VERSION 5.7 ;
  NOWIREEXTENSIONATPIN ON ;
  DIVIDERCHAR "/" ;
  BUSBITCHARS "[]" ;
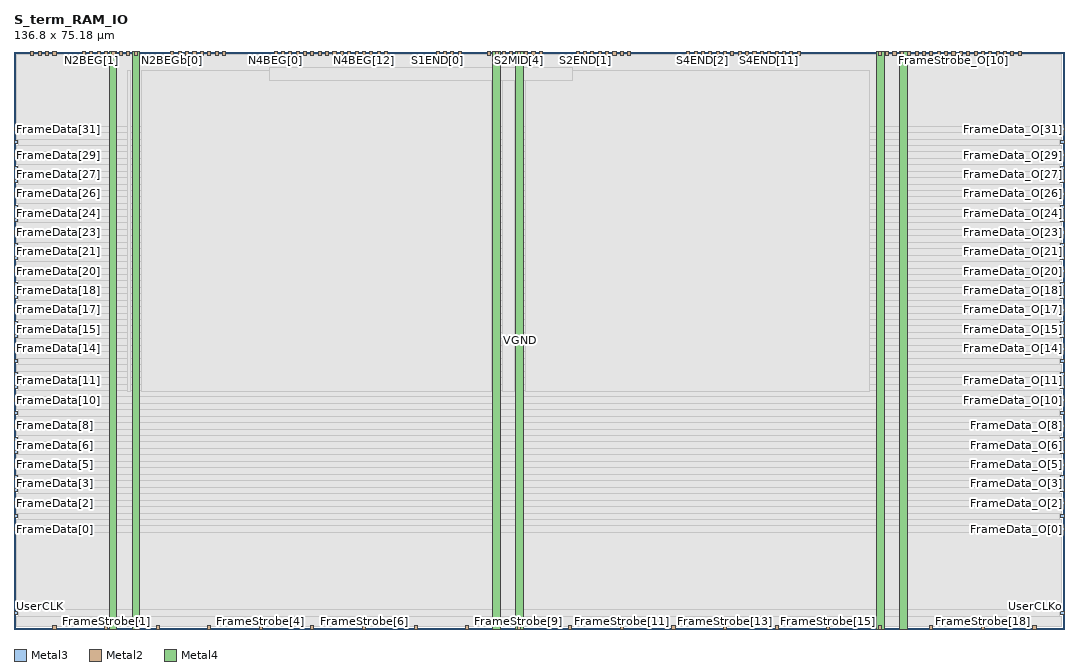
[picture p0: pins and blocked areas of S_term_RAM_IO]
MACRO S_term_RAM_IO
  CLASS BLOCK ;
  FOREIGN S_term_RAM_IO ;
  ORIGIN 0.000 0.000 ;
  SIZE 136.800 BY 75.180 ;
  PIN FrameData[0]
    DIRECTION INPUT ;
    USE SIGNAL ;
    ANTENNAGATEAREA 0.180700 ;
    PORT
      LAYER Metal3 ;
        RECT 0.000 12.820 0.400 13.220 ;
    END
  END FrameData[0]
  PIN FrameData[10]
    DIRECTION INPUT ;
    USE SIGNAL ;
    ANTENNAGATEAREA 0.180700 ;
    PORT
      LAYER Metal3 ;
        RECT 0.000 29.620 0.400 30.020 ;
    END
  END FrameData[10]
  PIN FrameData[11]
    DIRECTION INPUT ;
    USE SIGNAL ;
    ANTENNAGATEAREA 0.180700 ;
    PORT
      LAYER Metal3 ;
        RECT 0.000 31.300 0.400 31.700 ;
    END
  END FrameData[11]
  PIN FrameData[12]
    DIRECTION INPUT ;
    USE SIGNAL ;
    ANTENNAGATEAREA 0.180700 ;
    PORT
      LAYER Metal3 ;
        RECT 0.000 32.980 0.400 33.380 ;
    END
  END FrameData[12]
  PIN FrameData[13]
    DIRECTION INPUT ;
    USE SIGNAL ;
    ANTENNAGATEAREA 0.180700 ;
    PORT
      LAYER Metal3 ;
        RECT 0.000 34.660 0.400 35.060 ;
    END
  END FrameData[13]
  PIN FrameData[14]
    DIRECTION INPUT ;
    USE SIGNAL ;
    ANTENNAGATEAREA 0.180700 ;
    PORT
      LAYER Metal3 ;
        RECT 0.000 36.340 0.400 36.740 ;
    END
  END FrameData[14]
  PIN FrameData[15]
    DIRECTION INPUT ;
    USE SIGNAL ;
    ANTENNAGATEAREA 0.180700 ;
    PORT
      LAYER Metal3 ;
        RECT 0.000 38.020 0.400 38.420 ;
    END
  END FrameData[15]
  PIN FrameData[16]
    DIRECTION INPUT ;
    USE SIGNAL ;
    ANTENNAGATEAREA 0.180700 ;
    PORT
      LAYER Metal3 ;
        RECT 0.000 39.700 0.400 40.100 ;
    END
  END FrameData[16]
  PIN FrameData[17]
    DIRECTION INPUT ;
    USE SIGNAL ;
    ANTENNAGATEAREA 0.180700 ;
    PORT
      LAYER Metal3 ;
        RECT 0.000 41.380 0.400 41.780 ;
    END
  END FrameData[17]
  PIN FrameData[18]
    DIRECTION INPUT ;
    USE SIGNAL ;
    ANTENNAGATEAREA 0.180700 ;
    PORT
      LAYER Metal3 ;
        RECT 0.000 43.060 0.400 43.460 ;
    END
  END FrameData[18]
  PIN FrameData[19]
    DIRECTION INPUT ;
    USE SIGNAL ;
    ANTENNAGATEAREA 0.180700 ;
    PORT
      LAYER Metal3 ;
        RECT 0.000 44.740 0.400 45.140 ;
    END
  END FrameData[19]
  PIN FrameData[1]
    DIRECTION INPUT ;
    USE SIGNAL ;
    ANTENNAGATEAREA 0.180700 ;
    PORT
      LAYER Metal3 ;
        RECT 0.000 14.500 0.400 14.900 ;
    END
  END FrameData[1]
  PIN FrameData[20]
    DIRECTION INPUT ;
    USE SIGNAL ;
    ANTENNAGATEAREA 0.180700 ;
    PORT
      LAYER Metal3 ;
        RECT 0.000 46.420 0.400 46.820 ;
    END
  END FrameData[20]
  PIN FrameData[21]
    DIRECTION INPUT ;
    USE SIGNAL ;
    ANTENNAGATEAREA 0.180700 ;
    PORT
      LAYER Metal3 ;
        RECT 0.000 48.100 0.400 48.500 ;
    END
  END FrameData[21]
  PIN FrameData[22]
    DIRECTION INPUT ;
    USE SIGNAL ;
    ANTENNAGATEAREA 0.180700 ;
    PORT
      LAYER Metal3 ;
        RECT 0.000 49.780 0.400 50.180 ;
    END
  END FrameData[22]
  PIN FrameData[23]
    DIRECTION INPUT ;
    USE SIGNAL ;
    ANTENNAGATEAREA 0.180700 ;
    PORT
      LAYER Metal3 ;
        RECT 0.000 51.460 0.400 51.860 ;
    END
  END FrameData[23]
  PIN FrameData[24]
    DIRECTION INPUT ;
    USE SIGNAL ;
    ANTENNAGATEAREA 0.180700 ;
    PORT
      LAYER Metal3 ;
        RECT 0.000 53.140 0.400 53.540 ;
    END
  END FrameData[24]
  PIN FrameData[25]
    DIRECTION INPUT ;
    USE SIGNAL ;
    ANTENNAGATEAREA 0.180700 ;
    PORT
      LAYER Metal3 ;
        RECT 0.000 54.820 0.400 55.220 ;
    END
  END FrameData[25]
  PIN FrameData[26]
    DIRECTION INPUT ;
    USE SIGNAL ;
    ANTENNAGATEAREA 0.180700 ;
    PORT
      LAYER Metal3 ;
        RECT 0.000 56.500 0.400 56.900 ;
    END
  END FrameData[26]
  PIN FrameData[27]
    DIRECTION INPUT ;
    USE SIGNAL ;
    ANTENNAGATEAREA 0.180700 ;
    PORT
      LAYER Metal3 ;
        RECT 0.000 58.180 0.400 58.580 ;
    END
  END FrameData[27]
  PIN FrameData[28]
    DIRECTION INPUT ;
    USE SIGNAL ;
    ANTENNAGATEAREA 0.180700 ;
    PORT
      LAYER Metal3 ;
        RECT 0.000 59.860 0.400 60.260 ;
    END
  END FrameData[28]
  PIN FrameData[29]
    DIRECTION INPUT ;
    USE SIGNAL ;
    ANTENNAGATEAREA 0.180700 ;
    PORT
      LAYER Metal3 ;
        RECT 0.000 61.540 0.400 61.940 ;
    END
  END FrameData[29]
  PIN FrameData[2]
    DIRECTION INPUT ;
    USE SIGNAL ;
    ANTENNAGATEAREA 0.180700 ;
    PORT
      LAYER Metal3 ;
        RECT 0.000 16.180 0.400 16.580 ;
    END
  END FrameData[2]
  PIN FrameData[30]
    DIRECTION INPUT ;
    USE SIGNAL ;
    ANTENNAGATEAREA 0.180700 ;
    PORT
      LAYER Metal3 ;
        RECT 0.000 63.220 0.400 63.620 ;
    END
  END FrameData[30]
  PIN FrameData[31]
    DIRECTION INPUT ;
    USE SIGNAL ;
    ANTENNAGATEAREA 0.180700 ;
    PORT
      LAYER Metal3 ;
        RECT 0.000 64.900 0.400 65.300 ;
    END
  END FrameData[31]
  PIN FrameData[3]
    DIRECTION INPUT ;
    USE SIGNAL ;
    ANTENNAGATEAREA 0.180700 ;
    PORT
      LAYER Metal3 ;
        RECT 0.000 17.860 0.400 18.260 ;
    END
  END FrameData[3]
  PIN FrameData[4]
    DIRECTION INPUT ;
    USE SIGNAL ;
    ANTENNAGATEAREA 0.180700 ;
    PORT
      LAYER Metal3 ;
        RECT 0.000 19.540 0.400 19.940 ;
    END
  END FrameData[4]
  PIN FrameData[5]
    DIRECTION INPUT ;
    USE SIGNAL ;
    ANTENNAGATEAREA 0.180700 ;
    PORT
      LAYER Metal3 ;
        RECT 0.000 21.220 0.400 21.620 ;
    END
  END FrameData[5]
  PIN FrameData[6]
    DIRECTION INPUT ;
    USE SIGNAL ;
    ANTENNAGATEAREA 0.180700 ;
    PORT
      LAYER Metal3 ;
        RECT 0.000 22.900 0.400 23.300 ;
    END
  END FrameData[6]
  PIN FrameData[7]
    DIRECTION INPUT ;
    USE SIGNAL ;
    ANTENNAGATEAREA 0.180700 ;
    PORT
      LAYER Metal3 ;
        RECT 0.000 24.580 0.400 24.980 ;
    END
  END FrameData[7]
  PIN FrameData[8]
    DIRECTION INPUT ;
    USE SIGNAL ;
    ANTENNAGATEAREA 0.180700 ;
    PORT
      LAYER Metal3 ;
        RECT 0.000 26.260 0.400 26.660 ;
    END
  END FrameData[8]
  PIN FrameData[9]
    DIRECTION INPUT ;
    USE SIGNAL ;
    ANTENNAGATEAREA 0.180700 ;
    PORT
      LAYER Metal3 ;
        RECT 0.000 27.940 0.400 28.340 ;
    END
  END FrameData[9]
  PIN FrameData_O[0]
    DIRECTION OUTPUT ;
    USE SIGNAL ;
    ANTENNADIFFAREA 2.724000 ;
    PORT
      LAYER Metal3 ;
        RECT 136.400 12.820 136.800 13.220 ;
    END
  END FrameData_O[0]
  PIN FrameData_O[10]
    DIRECTION OUTPUT ;
    USE SIGNAL ;
    ANTENNADIFFAREA 2.724000 ;
    PORT
      LAYER Metal3 ;
        RECT 136.400 29.620 136.800 30.020 ;
    END
  END FrameData_O[10]
  PIN FrameData_O[11]
    DIRECTION OUTPUT ;
    USE SIGNAL ;
    ANTENNADIFFAREA 2.724000 ;
    PORT
      LAYER Metal3 ;
        RECT 136.400 31.300 136.800 31.700 ;
    END
  END FrameData_O[11]
  PIN FrameData_O[12]
    DIRECTION OUTPUT ;
    USE SIGNAL ;
    ANTENNADIFFAREA 2.724000 ;
    PORT
      LAYER Metal3 ;
        RECT 136.400 32.980 136.800 33.380 ;
    END
  END FrameData_O[12]
  PIN FrameData_O[13]
    DIRECTION OUTPUT ;
    USE SIGNAL ;
    ANTENNADIFFAREA 2.724000 ;
    PORT
      LAYER Metal3 ;
        RECT 136.400 34.660 136.800 35.060 ;
    END
  END FrameData_O[13]
  PIN FrameData_O[14]
    DIRECTION OUTPUT ;
    USE SIGNAL ;
    ANTENNADIFFAREA 2.724000 ;
    PORT
      LAYER Metal3 ;
        RECT 136.400 36.340 136.800 36.740 ;
    END
  END FrameData_O[14]
  PIN FrameData_O[15]
    DIRECTION OUTPUT ;
    USE SIGNAL ;
    ANTENNADIFFAREA 2.724000 ;
    PORT
      LAYER Metal3 ;
        RECT 136.400 38.020 136.800 38.420 ;
    END
  END FrameData_O[15]
  PIN FrameData_O[16]
    DIRECTION OUTPUT ;
    USE SIGNAL ;
    ANTENNADIFFAREA 2.724000 ;
    PORT
      LAYER Metal3 ;
        RECT 136.400 39.700 136.800 40.100 ;
    END
  END FrameData_O[16]
  PIN FrameData_O[17]
    DIRECTION OUTPUT ;
    USE SIGNAL ;
    ANTENNADIFFAREA 2.724000 ;
    PORT
      LAYER Metal3 ;
        RECT 136.400 41.380 136.800 41.780 ;
    END
  END FrameData_O[17]
  PIN FrameData_O[18]
    DIRECTION OUTPUT ;
    USE SIGNAL ;
    ANTENNADIFFAREA 2.724000 ;
    PORT
      LAYER Metal3 ;
        RECT 136.400 43.060 136.800 43.460 ;
    END
  END FrameData_O[18]
  PIN FrameData_O[19]
    DIRECTION OUTPUT ;
    USE SIGNAL ;
    ANTENNADIFFAREA 2.724000 ;
    PORT
      LAYER Metal3 ;
        RECT 136.400 44.740 136.800 45.140 ;
    END
  END FrameData_O[19]
  PIN FrameData_O[1]
    DIRECTION OUTPUT ;
    USE SIGNAL ;
    ANTENNADIFFAREA 2.724000 ;
    PORT
      LAYER Metal3 ;
        RECT 136.400 14.500 136.800 14.900 ;
    END
  END FrameData_O[1]
  PIN FrameData_O[20]
    DIRECTION OUTPUT ;
    USE SIGNAL ;
    ANTENNADIFFAREA 2.724000 ;
    PORT
      LAYER Metal3 ;
        RECT 136.400 46.420 136.800 46.820 ;
    END
  END FrameData_O[20]
  PIN FrameData_O[21]
    DIRECTION OUTPUT ;
    USE SIGNAL ;
    ANTENNADIFFAREA 2.724000 ;
    PORT
      LAYER Metal3 ;
        RECT 136.400 48.100 136.800 48.500 ;
    END
  END FrameData_O[21]
  PIN FrameData_O[22]
    DIRECTION OUTPUT ;
    USE SIGNAL ;
    ANTENNADIFFAREA 2.724000 ;
    PORT
      LAYER Metal3 ;
        RECT 136.400 49.780 136.800 50.180 ;
    END
  END FrameData_O[22]
  PIN FrameData_O[23]
    DIRECTION OUTPUT ;
    USE SIGNAL ;
    ANTENNADIFFAREA 2.724000 ;
    PORT
      LAYER Metal3 ;
        RECT 136.400 51.460 136.800 51.860 ;
    END
  END FrameData_O[23]
  PIN FrameData_O[24]
    DIRECTION OUTPUT ;
    USE SIGNAL ;
    ANTENNADIFFAREA 2.724000 ;
    PORT
      LAYER Metal3 ;
        RECT 136.400 53.140 136.800 53.540 ;
    END
  END FrameData_O[24]
  PIN FrameData_O[25]
    DIRECTION OUTPUT ;
    USE SIGNAL ;
    ANTENNADIFFAREA 2.724000 ;
    PORT
      LAYER Metal3 ;
        RECT 136.400 54.820 136.800 55.220 ;
    END
  END FrameData_O[25]
  PIN FrameData_O[26]
    DIRECTION OUTPUT ;
    USE SIGNAL ;
    ANTENNADIFFAREA 2.724000 ;
    PORT
      LAYER Metal3 ;
        RECT 136.400 56.500 136.800 56.900 ;
    END
  END FrameData_O[26]
  PIN FrameData_O[27]
    DIRECTION OUTPUT ;
    USE SIGNAL ;
    ANTENNADIFFAREA 2.724000 ;
    PORT
      LAYER Metal3 ;
        RECT 136.400 58.180 136.800 58.580 ;
    END
  END FrameData_O[27]
  PIN FrameData_O[28]
    DIRECTION OUTPUT ;
    USE SIGNAL ;
    ANTENNADIFFAREA 2.724000 ;
    PORT
      LAYER Metal3 ;
        RECT 136.400 59.860 136.800 60.260 ;
    END
  END FrameData_O[28]
  PIN FrameData_O[29]
    DIRECTION OUTPUT ;
    USE SIGNAL ;
    ANTENNADIFFAREA 2.724000 ;
    PORT
      LAYER Metal3 ;
        RECT 136.400 61.540 136.800 61.940 ;
    END
  END FrameData_O[29]
  PIN FrameData_O[2]
    DIRECTION OUTPUT ;
    USE SIGNAL ;
    ANTENNADIFFAREA 2.724000 ;
    PORT
      LAYER Metal3 ;
        RECT 136.400 16.180 136.800 16.580 ;
    END
  END FrameData_O[2]
  PIN FrameData_O[30]
    DIRECTION OUTPUT ;
    USE SIGNAL ;
    ANTENNADIFFAREA 2.724000 ;
    PORT
      LAYER Metal3 ;
        RECT 136.400 63.220 136.800 63.620 ;
    END
  END FrameData_O[30]
  PIN FrameData_O[31]
    DIRECTION OUTPUT ;
    USE SIGNAL ;
    ANTENNADIFFAREA 2.724000 ;
    PORT
      LAYER Metal3 ;
        RECT 136.400 64.900 136.800 65.300 ;
    END
  END FrameData_O[31]
  PIN FrameData_O[3]
    DIRECTION OUTPUT ;
    USE SIGNAL ;
    ANTENNADIFFAREA 2.724000 ;
    PORT
      LAYER Metal3 ;
        RECT 136.400 17.860 136.800 18.260 ;
    END
  END FrameData_O[3]
  PIN FrameData_O[4]
    DIRECTION OUTPUT ;
    USE SIGNAL ;
    ANTENNADIFFAREA 2.724000 ;
    PORT
      LAYER Metal3 ;
        RECT 136.400 19.540 136.800 19.940 ;
    END
  END FrameData_O[4]
  PIN FrameData_O[5]
    DIRECTION OUTPUT ;
    USE SIGNAL ;
    ANTENNADIFFAREA 2.724000 ;
    PORT
      LAYER Metal3 ;
        RECT 136.400 21.220 136.800 21.620 ;
    END
  END FrameData_O[5]
  PIN FrameData_O[6]
    DIRECTION OUTPUT ;
    USE SIGNAL ;
    ANTENNADIFFAREA 2.724000 ;
    PORT
      LAYER Metal3 ;
        RECT 136.400 22.900 136.800 23.300 ;
    END
  END FrameData_O[6]
  PIN FrameData_O[7]
    DIRECTION OUTPUT ;
    USE SIGNAL ;
    ANTENNADIFFAREA 2.724000 ;
    PORT
      LAYER Metal3 ;
        RECT 136.400 24.580 136.800 24.980 ;
    END
  END FrameData_O[7]
  PIN FrameData_O[8]
    DIRECTION OUTPUT ;
    USE SIGNAL ;
    ANTENNADIFFAREA 2.724000 ;
    PORT
      LAYER Metal3 ;
        RECT 136.400 26.260 136.800 26.660 ;
    END
  END FrameData_O[8]
  PIN FrameData_O[9]
    DIRECTION OUTPUT ;
    USE SIGNAL ;
    ANTENNADIFFAREA 2.724000 ;
    PORT
      LAYER Metal3 ;
        RECT 136.400 27.940 136.800 28.340 ;
    END
  END FrameData_O[9]
  PIN FrameStrobe[0]
    DIRECTION INPUT ;
    USE SIGNAL ;
    ANTENNAGATEAREA 0.180700 ;
    PORT
      LAYER Metal2 ;
        RECT 5.080 0.000 5.480 0.400 ;
    END
  END FrameStrobe[0]
  PIN FrameStrobe[10]
    DIRECTION INPUT ;
    USE SIGNAL ;
    ANTENNAGATEAREA 0.180700 ;
    PORT
      LAYER Metal2 ;
        RECT 72.280 0.000 72.680 0.400 ;
    END
  END FrameStrobe[10]
  PIN FrameStrobe[11]
    DIRECTION INPUT ;
    USE SIGNAL ;
    ANTENNAGATEAREA 0.180700 ;
    PORT
      LAYER Metal2 ;
        RECT 79.000 0.000 79.400 0.400 ;
    END
  END FrameStrobe[11]
  PIN FrameStrobe[12]
    DIRECTION INPUT ;
    USE SIGNAL ;
    ANTENNAGATEAREA 0.180700 ;
    PORT
      LAYER Metal2 ;
        RECT 85.720 0.000 86.120 0.400 ;
    END
  END FrameStrobe[12]
  PIN FrameStrobe[13]
    DIRECTION INPUT ;
    USE SIGNAL ;
    ANTENNAGATEAREA 0.180700 ;
    PORT
      LAYER Metal2 ;
        RECT 92.440 0.000 92.840 0.400 ;
    END
  END FrameStrobe[13]
  PIN FrameStrobe[14]
    DIRECTION INPUT ;
    USE SIGNAL ;
    ANTENNAGATEAREA 0.180700 ;
    PORT
      LAYER Metal2 ;
        RECT 99.160 0.000 99.560 0.400 ;
    END
  END FrameStrobe[14]
  PIN FrameStrobe[15]
    DIRECTION INPUT ;
    USE SIGNAL ;
    ANTENNAGATEAREA 0.180700 ;
    PORT
      LAYER Metal2 ;
        RECT 105.880 0.000 106.280 0.400 ;
    END
  END FrameStrobe[15]
  PIN FrameStrobe[16]
    DIRECTION INPUT ;
    USE SIGNAL ;
    ANTENNAGATEAREA 0.180700 ;
    PORT
      LAYER Metal2 ;
        RECT 112.600 0.000 113.000 0.400 ;
    END
  END FrameStrobe[16]
  PIN FrameStrobe[17]
    DIRECTION INPUT ;
    USE SIGNAL ;
    ANTENNAGATEAREA 0.180700 ;
    PORT
      LAYER Metal2 ;
        RECT 119.320 0.000 119.720 0.400 ;
    END
  END FrameStrobe[17]
  PIN FrameStrobe[18]
    DIRECTION INPUT ;
    USE SIGNAL ;
    ANTENNAGATEAREA 0.180700 ;
    PORT
      LAYER Metal2 ;
        RECT 126.040 0.000 126.440 0.400 ;
    END
  END FrameStrobe[18]
  PIN FrameStrobe[19]
    DIRECTION INPUT ;
    USE SIGNAL ;
    ANTENNAGATEAREA 0.180700 ;
    PORT
      LAYER Metal2 ;
        RECT 132.760 0.000 133.160 0.400 ;
    END
  END FrameStrobe[19]
  PIN FrameStrobe[1]
    DIRECTION INPUT ;
    USE SIGNAL ;
    ANTENNAGATEAREA 0.180700 ;
    PORT
      LAYER Metal2 ;
        RECT 11.800 0.000 12.200 0.400 ;
    END
  END FrameStrobe[1]
  PIN FrameStrobe[2]
    DIRECTION INPUT ;
    USE SIGNAL ;
    ANTENNAGATEAREA 0.180700 ;
    PORT
      LAYER Metal2 ;
        RECT 18.520 0.000 18.920 0.400 ;
    END
  END FrameStrobe[2]
  PIN FrameStrobe[3]
    DIRECTION INPUT ;
    USE SIGNAL ;
    ANTENNAGATEAREA 0.180700 ;
    PORT
      LAYER Metal2 ;
        RECT 25.240 0.000 25.640 0.400 ;
    END
  END FrameStrobe[3]
  PIN FrameStrobe[4]
    DIRECTION INPUT ;
    USE SIGNAL ;
    ANTENNAGATEAREA 0.180700 ;
    PORT
      LAYER Metal2 ;
        RECT 31.960 0.000 32.360 0.400 ;
    END
  END FrameStrobe[4]
  PIN FrameStrobe[5]
    DIRECTION INPUT ;
    USE SIGNAL ;
    ANTENNAGATEAREA 0.180700 ;
    PORT
      LAYER Metal2 ;
        RECT 38.680 0.000 39.080 0.400 ;
    END
  END FrameStrobe[5]
  PIN FrameStrobe[6]
    DIRECTION INPUT ;
    USE SIGNAL ;
    ANTENNAGATEAREA 0.180700 ;
    PORT
      LAYER Metal2 ;
        RECT 45.400 0.000 45.800 0.400 ;
    END
  END FrameStrobe[6]
  PIN FrameStrobe[7]
    DIRECTION INPUT ;
    USE SIGNAL ;
    ANTENNAGATEAREA 0.180700 ;
    PORT
      LAYER Metal2 ;
        RECT 52.120 0.000 52.520 0.400 ;
    END
  END FrameStrobe[7]
  PIN FrameStrobe[8]
    DIRECTION INPUT ;
    USE SIGNAL ;
    ANTENNAGATEAREA 0.180700 ;
    PORT
      LAYER Metal2 ;
        RECT 58.840 0.000 59.240 0.400 ;
    END
  END FrameStrobe[8]
  PIN FrameStrobe[9]
    DIRECTION INPUT ;
    USE SIGNAL ;
    ANTENNAGATEAREA 0.180700 ;
    PORT
      LAYER Metal2 ;
        RECT 65.560 0.000 65.960 0.400 ;
    END
  END FrameStrobe[9]
  PIN FrameStrobe_O[0]
    DIRECTION OUTPUT ;
    USE SIGNAL ;
    ANTENNADIFFAREA 2.724000 ;
    PORT
      LAYER Metal2 ;
        RECT 112.600 74.780 113.000 75.180 ;
    END
  END FrameStrobe_O[0]
  PIN FrameStrobe_O[10]
    DIRECTION OUTPUT ;
    USE SIGNAL ;
    ANTENNADIFFAREA 2.724000 ;
    PORT
      LAYER Metal2 ;
        RECT 122.200 74.780 122.600 75.180 ;
    END
  END FrameStrobe_O[10]
  PIN FrameStrobe_O[11]
    DIRECTION OUTPUT ;
    USE SIGNAL ;
    ANTENNADIFFAREA 2.724000 ;
    PORT
      LAYER Metal2 ;
        RECT 123.160 74.780 123.560 75.180 ;
    END
  END FrameStrobe_O[11]
  PIN FrameStrobe_O[12]
    DIRECTION OUTPUT ;
    USE SIGNAL ;
    ANTENNADIFFAREA 2.724000 ;
    PORT
      LAYER Metal2 ;
        RECT 124.120 74.780 124.520 75.180 ;
    END
  END FrameStrobe_O[12]
  PIN FrameStrobe_O[13]
    DIRECTION OUTPUT ;
    USE SIGNAL ;
    ANTENNADIFFAREA 2.724000 ;
    PORT
      LAYER Metal2 ;
        RECT 125.080 74.780 125.480 75.180 ;
    END
  END FrameStrobe_O[13]
  PIN FrameStrobe_O[14]
    DIRECTION OUTPUT ;
    USE SIGNAL ;
    ANTENNADIFFAREA 2.724000 ;
    PORT
      LAYER Metal2 ;
        RECT 126.040 74.780 126.440 75.180 ;
    END
  END FrameStrobe_O[14]
  PIN FrameStrobe_O[15]
    DIRECTION OUTPUT ;
    USE SIGNAL ;
    ANTENNADIFFAREA 2.724000 ;
    PORT
      LAYER Metal2 ;
        RECT 127.000 74.780 127.400 75.180 ;
    END
  END FrameStrobe_O[15]
  PIN FrameStrobe_O[16]
    DIRECTION OUTPUT ;
    USE SIGNAL ;
    ANTENNADIFFAREA 2.724000 ;
    PORT
      LAYER Metal2 ;
        RECT 127.960 74.780 128.360 75.180 ;
    END
  END FrameStrobe_O[16]
  PIN FrameStrobe_O[17]
    DIRECTION OUTPUT ;
    USE SIGNAL ;
    ANTENNADIFFAREA 2.724000 ;
    PORT
      LAYER Metal2 ;
        RECT 128.920 74.780 129.320 75.180 ;
    END
  END FrameStrobe_O[17]
  PIN FrameStrobe_O[18]
    DIRECTION OUTPUT ;
    USE SIGNAL ;
    ANTENNADIFFAREA 2.724000 ;
    PORT
      LAYER Metal2 ;
        RECT 129.880 74.780 130.280 75.180 ;
    END
  END FrameStrobe_O[18]
  PIN FrameStrobe_O[19]
    DIRECTION OUTPUT ;
    USE SIGNAL ;
    ANTENNADIFFAREA 2.724000 ;
    PORT
      LAYER Metal2 ;
        RECT 130.840 74.780 131.240 75.180 ;
    END
  END FrameStrobe_O[19]
  PIN FrameStrobe_O[1]
    DIRECTION OUTPUT ;
    USE SIGNAL ;
    ANTENNADIFFAREA 2.724000 ;
    PORT
      LAYER Metal2 ;
        RECT 113.560 74.780 113.960 75.180 ;
    END
  END FrameStrobe_O[1]
  PIN FrameStrobe_O[2]
    DIRECTION OUTPUT ;
    USE SIGNAL ;
    ANTENNADIFFAREA 2.724000 ;
    PORT
      LAYER Metal2 ;
        RECT 114.520 74.780 114.920 75.180 ;
    END
  END FrameStrobe_O[2]
  PIN FrameStrobe_O[3]
    DIRECTION OUTPUT ;
    USE SIGNAL ;
    ANTENNADIFFAREA 2.724000 ;
    PORT
      LAYER Metal2 ;
        RECT 115.480 74.780 115.880 75.180 ;
    END
  END FrameStrobe_O[3]
  PIN FrameStrobe_O[4]
    DIRECTION OUTPUT ;
    USE SIGNAL ;
    ANTENNADIFFAREA 2.724000 ;
    PORT
      LAYER Metal2 ;
        RECT 116.440 74.780 116.840 75.180 ;
    END
  END FrameStrobe_O[4]
  PIN FrameStrobe_O[5]
    DIRECTION OUTPUT ;
    USE SIGNAL ;
    ANTENNADIFFAREA 2.724000 ;
    PORT
      LAYER Metal2 ;
        RECT 117.400 74.780 117.800 75.180 ;
    END
  END FrameStrobe_O[5]
  PIN FrameStrobe_O[6]
    DIRECTION OUTPUT ;
    USE SIGNAL ;
    ANTENNADIFFAREA 2.724000 ;
    PORT
      LAYER Metal2 ;
        RECT 118.360 74.780 118.760 75.180 ;
    END
  END FrameStrobe_O[6]
  PIN FrameStrobe_O[7]
    DIRECTION OUTPUT ;
    USE SIGNAL ;
    ANTENNADIFFAREA 2.724000 ;
    PORT
      LAYER Metal2 ;
        RECT 119.320 74.780 119.720 75.180 ;
    END
  END FrameStrobe_O[7]
  PIN FrameStrobe_O[8]
    DIRECTION OUTPUT ;
    USE SIGNAL ;
    ANTENNADIFFAREA 2.724000 ;
    PORT
      LAYER Metal2 ;
        RECT 120.280 74.780 120.680 75.180 ;
    END
  END FrameStrobe_O[8]
  PIN FrameStrobe_O[9]
    DIRECTION OUTPUT ;
    USE SIGNAL ;
    ANTENNADIFFAREA 2.724000 ;
    PORT
      LAYER Metal2 ;
        RECT 121.240 74.780 121.640 75.180 ;
    END
  END FrameStrobe_O[9]
  PIN N1BEG[0]
    DIRECTION OUTPUT ;
    USE SIGNAL ;
    ANTENNADIFFAREA 2.724000 ;
    PORT
      LAYER Metal2 ;
        RECT 2.200 74.780 2.600 75.180 ;
    END
  END N1BEG[0]
  PIN N1BEG[1]
    DIRECTION OUTPUT ;
    USE SIGNAL ;
    ANTENNADIFFAREA 2.724000 ;
    PORT
      LAYER Metal2 ;
        RECT 3.160 74.780 3.560 75.180 ;
    END
  END N1BEG[1]
  PIN N1BEG[2]
    DIRECTION OUTPUT ;
    USE SIGNAL ;
    ANTENNADIFFAREA 2.724000 ;
    PORT
      LAYER Metal2 ;
        RECT 4.120 74.780 4.520 75.180 ;
    END
  END N1BEG[2]
  PIN N1BEG[3]
    DIRECTION OUTPUT ;
    USE SIGNAL ;
    ANTENNADIFFAREA 2.724000 ;
    PORT
      LAYER Metal2 ;
        RECT 5.080 74.780 5.480 75.180 ;
    END
  END N1BEG[3]
  PIN N2BEG[0]
    DIRECTION OUTPUT ;
    USE SIGNAL ;
    ANTENNADIFFAREA 2.724000 ;
    PORT
      LAYER Metal2 ;
        RECT 8.920 74.780 9.320 75.180 ;
    END
  END N2BEG[0]
  PIN N2BEG[1]
    DIRECTION OUTPUT ;
    USE SIGNAL ;
    ANTENNADIFFAREA 2.724000 ;
    PORT
      LAYER Metal2 ;
        RECT 9.880 74.780 10.280 75.180 ;
    END
  END N2BEG[1]
  PIN N2BEG[2]
    DIRECTION OUTPUT ;
    USE SIGNAL ;
    ANTENNADIFFAREA 2.724000 ;
    PORT
      LAYER Metal2 ;
        RECT 10.840 74.780 11.240 75.180 ;
    END
  END N2BEG[2]
  PIN N2BEG[3]
    DIRECTION OUTPUT ;
    USE SIGNAL ;
    ANTENNADIFFAREA 2.724000 ;
    PORT
      LAYER Metal2 ;
        RECT 11.800 74.780 12.200 75.180 ;
    END
  END N2BEG[3]
  PIN N2BEG[4]
    DIRECTION OUTPUT ;
    USE SIGNAL ;
    ANTENNADIFFAREA 2.724000 ;
    PORT
      LAYER Metal2 ;
        RECT 12.760 74.780 13.160 75.180 ;
    END
  END N2BEG[4]
  PIN N2BEG[5]
    DIRECTION OUTPUT ;
    USE SIGNAL ;
    ANTENNADIFFAREA 2.724000 ;
    PORT
      LAYER Metal2 ;
        RECT 13.720 74.780 14.120 75.180 ;
    END
  END N2BEG[5]
  PIN N2BEG[6]
    DIRECTION OUTPUT ;
    USE SIGNAL ;
    ANTENNADIFFAREA 2.724000 ;
    PORT
      LAYER Metal2 ;
        RECT 14.680 74.780 15.080 75.180 ;
    END
  END N2BEG[6]
  PIN N2BEG[7]
    DIRECTION OUTPUT ;
    USE SIGNAL ;
    ANTENNADIFFAREA 2.724000 ;
    PORT
      LAYER Metal2 ;
        RECT 15.640 74.780 16.040 75.180 ;
    END
  END N2BEG[7]
  PIN N2BEGb[0]
    DIRECTION OUTPUT ;
    USE SIGNAL ;
    ANTENNADIFFAREA 2.724000 ;
    PORT
      LAYER Metal2 ;
        RECT 20.440 74.780 20.840 75.180 ;
    END
  END N2BEGb[0]
  PIN N2BEGb[1]
    DIRECTION OUTPUT ;
    USE SIGNAL ;
    ANTENNADIFFAREA 2.724000 ;
    PORT
      LAYER Metal2 ;
        RECT 21.400 74.780 21.800 75.180 ;
    END
  END N2BEGb[1]
  PIN N2BEGb[2]
    DIRECTION OUTPUT ;
    USE SIGNAL ;
    ANTENNADIFFAREA 2.724000 ;
    PORT
      LAYER Metal2 ;
        RECT 22.360 74.780 22.760 75.180 ;
    END
  END N2BEGb[2]
  PIN N2BEGb[3]
    DIRECTION OUTPUT ;
    USE SIGNAL ;
    ANTENNADIFFAREA 2.724000 ;
    PORT
      LAYER Metal2 ;
        RECT 23.320 74.780 23.720 75.180 ;
    END
  END N2BEGb[3]
  PIN N2BEGb[4]
    DIRECTION OUTPUT ;
    USE SIGNAL ;
    ANTENNADIFFAREA 2.724000 ;
    PORT
      LAYER Metal2 ;
        RECT 24.280 74.780 24.680 75.180 ;
    END
  END N2BEGb[4]
  PIN N2BEGb[5]
    DIRECTION OUTPUT ;
    USE SIGNAL ;
    ANTENNADIFFAREA 2.724000 ;
    PORT
      LAYER Metal2 ;
        RECT 25.240 74.780 25.640 75.180 ;
    END
  END N2BEGb[5]
  PIN N2BEGb[6]
    DIRECTION OUTPUT ;
    USE SIGNAL ;
    ANTENNADIFFAREA 2.724000 ;
    PORT
      LAYER Metal2 ;
        RECT 26.200 74.780 26.600 75.180 ;
    END
  END N2BEGb[6]
  PIN N2BEGb[7]
    DIRECTION OUTPUT ;
    USE SIGNAL ;
    ANTENNADIFFAREA 2.724000 ;
    PORT
      LAYER Metal2 ;
        RECT 27.160 74.780 27.560 75.180 ;
    END
  END N2BEGb[7]
  PIN N4BEG[0]
    DIRECTION OUTPUT ;
    USE SIGNAL ;
    ANTENNADIFFAREA 2.724000 ;
    PORT
      LAYER Metal2 ;
        RECT 33.880 74.780 34.280 75.180 ;
    END
  END N4BEG[0]
  PIN N4BEG[10]
    DIRECTION OUTPUT ;
    USE SIGNAL ;
    ANTENNADIFFAREA 2.724000 ;
    PORT
      LAYER Metal2 ;
        RECT 43.480 74.780 43.880 75.180 ;
    END
  END N4BEG[10]
  PIN N4BEG[11]
    DIRECTION OUTPUT ;
    USE SIGNAL ;
    ANTENNADIFFAREA 2.724000 ;
    PORT
      LAYER Metal2 ;
        RECT 44.440 74.780 44.840 75.180 ;
    END
  END N4BEG[11]
  PIN N4BEG[12]
    DIRECTION OUTPUT ;
    USE SIGNAL ;
    ANTENNADIFFAREA 2.724000 ;
    PORT
      LAYER Metal2 ;
        RECT 45.400 74.780 45.800 75.180 ;
    END
  END N4BEG[12]
  PIN N4BEG[13]
    DIRECTION OUTPUT ;
    USE SIGNAL ;
    ANTENNADIFFAREA 2.724000 ;
    PORT
      LAYER Metal2 ;
        RECT 46.360 74.780 46.760 75.180 ;
    END
  END N4BEG[13]
  PIN N4BEG[14]
    DIRECTION OUTPUT ;
    USE SIGNAL ;
    ANTENNADIFFAREA 2.724000 ;
    PORT
      LAYER Metal2 ;
        RECT 47.320 74.780 47.720 75.180 ;
    END
  END N4BEG[14]
  PIN N4BEG[15]
    DIRECTION OUTPUT ;
    USE SIGNAL ;
    ANTENNADIFFAREA 2.724000 ;
    PORT
      LAYER Metal2 ;
        RECT 48.280 74.780 48.680 75.180 ;
    END
  END N4BEG[15]
  PIN N4BEG[1]
    DIRECTION OUTPUT ;
    USE SIGNAL ;
    ANTENNADIFFAREA 2.724000 ;
    PORT
      LAYER Metal2 ;
        RECT 34.840 74.780 35.240 75.180 ;
    END
  END N4BEG[1]
  PIN N4BEG[2]
    DIRECTION OUTPUT ;
    USE SIGNAL ;
    ANTENNADIFFAREA 2.724000 ;
    PORT
      LAYER Metal2 ;
        RECT 35.800 74.780 36.200 75.180 ;
    END
  END N4BEG[2]
  PIN N4BEG[3]
    DIRECTION OUTPUT ;
    USE SIGNAL ;
    ANTENNADIFFAREA 2.724000 ;
    PORT
      LAYER Metal2 ;
        RECT 36.760 74.780 37.160 75.180 ;
    END
  END N4BEG[3]
  PIN N4BEG[4]
    DIRECTION OUTPUT ;
    USE SIGNAL ;
    ANTENNADIFFAREA 2.724000 ;
    PORT
      LAYER Metal2 ;
        RECT 37.720 74.780 38.120 75.180 ;
    END
  END N4BEG[4]
  PIN N4BEG[5]
    DIRECTION OUTPUT ;
    USE SIGNAL ;
    ANTENNADIFFAREA 2.724000 ;
    PORT
      LAYER Metal2 ;
        RECT 38.680 74.780 39.080 75.180 ;
    END
  END N4BEG[5]
  PIN N4BEG[6]
    DIRECTION OUTPUT ;
    USE SIGNAL ;
    ANTENNADIFFAREA 2.724000 ;
    PORT
      LAYER Metal2 ;
        RECT 39.640 74.780 40.040 75.180 ;
    END
  END N4BEG[6]
  PIN N4BEG[7]
    DIRECTION OUTPUT ;
    USE SIGNAL ;
    ANTENNADIFFAREA 2.724000 ;
    PORT
      LAYER Metal2 ;
        RECT 40.600 74.780 41.000 75.180 ;
    END
  END N4BEG[7]
  PIN N4BEG[8]
    DIRECTION OUTPUT ;
    USE SIGNAL ;
    ANTENNADIFFAREA 2.724000 ;
    PORT
      LAYER Metal2 ;
        RECT 41.560 74.780 41.960 75.180 ;
    END
  END N4BEG[8]
  PIN N4BEG[9]
    DIRECTION OUTPUT ;
    USE SIGNAL ;
    ANTENNADIFFAREA 2.724000 ;
    PORT
      LAYER Metal2 ;
        RECT 42.520 74.780 42.920 75.180 ;
    END
  END N4BEG[9]
  PIN S1END[0]
    DIRECTION INPUT ;
    USE SIGNAL ;
    ANTENNAGATEAREA 0.180700 ;
    PORT
      LAYER Metal2 ;
        RECT 55.000 74.780 55.400 75.180 ;
    END
  END S1END[0]
  PIN S1END[1]
    DIRECTION INPUT ;
    USE SIGNAL ;
    ANTENNAGATEAREA 0.180700 ;
    PORT
      LAYER Metal2 ;
        RECT 55.960 74.780 56.360 75.180 ;
    END
  END S1END[1]
  PIN S1END[2]
    DIRECTION INPUT ;
    USE SIGNAL ;
    ANTENNAGATEAREA 0.180700 ;
    PORT
      LAYER Metal2 ;
        RECT 56.920 74.780 57.320 75.180 ;
    END
  END S1END[2]
  PIN S1END[3]
    DIRECTION INPUT ;
    USE SIGNAL ;
    ANTENNAGATEAREA 0.180700 ;
    PORT
      LAYER Metal2 ;
        RECT 57.880 74.780 58.280 75.180 ;
    END
  END S1END[3]
  PIN S2END[0]
    DIRECTION INPUT ;
    USE SIGNAL ;
    ANTENNAGATEAREA 0.180700 ;
    PORT
      LAYER Metal2 ;
        RECT 73.240 74.780 73.640 75.180 ;
    END
  END S2END[0]
  PIN S2END[1]
    DIRECTION INPUT ;
    USE SIGNAL ;
    ANTENNAGATEAREA 0.180700 ;
    PORT
      LAYER Metal2 ;
        RECT 74.200 74.780 74.600 75.180 ;
    END
  END S2END[1]
  PIN S2END[2]
    DIRECTION INPUT ;
    USE SIGNAL ;
    ANTENNAGATEAREA 0.180700 ;
    PORT
      LAYER Metal2 ;
        RECT 75.160 74.780 75.560 75.180 ;
    END
  END S2END[2]
  PIN S2END[3]
    DIRECTION INPUT ;
    USE SIGNAL ;
    ANTENNAGATEAREA 0.180700 ;
    PORT
      LAYER Metal2 ;
        RECT 76.120 74.780 76.520 75.180 ;
    END
  END S2END[3]
  PIN S2END[4]
    DIRECTION INPUT ;
    USE SIGNAL ;
    ANTENNAGATEAREA 0.180700 ;
    PORT
      LAYER Metal2 ;
        RECT 77.080 74.780 77.480 75.180 ;
    END
  END S2END[4]
  PIN S2END[5]
    DIRECTION INPUT ;
    USE SIGNAL ;
    ANTENNAGATEAREA 0.180700 ;
    PORT
      LAYER Metal2 ;
        RECT 78.040 74.780 78.440 75.180 ;
    END
  END S2END[5]
  PIN S2END[6]
    DIRECTION INPUT ;
    USE SIGNAL ;
    ANTENNAGATEAREA 0.180700 ;
    PORT
      LAYER Metal2 ;
        RECT 79.000 74.780 79.400 75.180 ;
    END
  END S2END[6]
  PIN S2END[7]
    DIRECTION INPUT ;
    USE SIGNAL ;
    ANTENNAGATEAREA 0.180700 ;
    PORT
      LAYER Metal2 ;
        RECT 79.960 74.780 80.360 75.180 ;
    END
  END S2END[7]
  PIN S2MID[0]
    DIRECTION INPUT ;
    USE SIGNAL ;
    ANTENNAGATEAREA 0.180700 ;
    PORT
      LAYER Metal2 ;
        RECT 61.720 74.780 62.120 75.180 ;
    END
  END S2MID[0]
  PIN S2MID[1]
    DIRECTION INPUT ;
    USE SIGNAL ;
    ANTENNAGATEAREA 0.180700 ;
    PORT
      LAYER Metal2 ;
        RECT 62.680 74.780 63.080 75.180 ;
    END
  END S2MID[1]
  PIN S2MID[2]
    DIRECTION INPUT ;
    USE SIGNAL ;
    ANTENNAGATEAREA 0.180700 ;
    PORT
      LAYER Metal2 ;
        RECT 63.640 74.780 64.040 75.180 ;
    END
  END S2MID[2]
  PIN S2MID[3]
    DIRECTION INPUT ;
    USE SIGNAL ;
    ANTENNAGATEAREA 0.180700 ;
    PORT
      LAYER Metal2 ;
        RECT 64.600 74.780 65.000 75.180 ;
    END
  END S2MID[3]
  PIN S2MID[4]
    DIRECTION INPUT ;
    USE SIGNAL ;
    ANTENNAGATEAREA 0.180700 ;
    PORT
      LAYER Metal2 ;
        RECT 65.560 74.780 65.960 75.180 ;
    END
  END S2MID[4]
  PIN S2MID[5]
    DIRECTION INPUT ;
    USE SIGNAL ;
    ANTENNAGATEAREA 0.180700 ;
    PORT
      LAYER Metal2 ;
        RECT 66.520 74.780 66.920 75.180 ;
    END
  END S2MID[5]
  PIN S2MID[6]
    DIRECTION INPUT ;
    USE SIGNAL ;
    ANTENNAGATEAREA 0.180700 ;
    PORT
      LAYER Metal2 ;
        RECT 67.480 74.780 67.880 75.180 ;
    END
  END S2MID[6]
  PIN S2MID[7]
    DIRECTION INPUT ;
    USE SIGNAL ;
    ANTENNAGATEAREA 0.180700 ;
    PORT
      LAYER Metal2 ;
        RECT 68.440 74.780 68.840 75.180 ;
    END
  END S2MID[7]
  PIN S4END[0]
    DIRECTION INPUT ;
    USE SIGNAL ;
    ANTENNAGATEAREA 0.180700 ;
    PORT
      LAYER Metal2 ;
        RECT 87.640 74.780 88.040 75.180 ;
    END
  END S4END[0]
  PIN S4END[10]
    DIRECTION INPUT ;
    USE SIGNAL ;
    ANTENNAGATEAREA 0.180700 ;
    PORT
      LAYER Metal2 ;
        RECT 97.240 74.780 97.640 75.180 ;
    END
  END S4END[10]
  PIN S4END[11]
    DIRECTION INPUT ;
    USE SIGNAL ;
    ANTENNAGATEAREA 0.180700 ;
    PORT
      LAYER Metal2 ;
        RECT 98.200 74.780 98.600 75.180 ;
    END
  END S4END[11]
  PIN S4END[12]
    DIRECTION INPUT ;
    USE SIGNAL ;
    ANTENNAGATEAREA 0.180700 ;
    PORT
      LAYER Metal2 ;
        RECT 99.160 74.780 99.560 75.180 ;
    END
  END S4END[12]
  PIN S4END[13]
    DIRECTION INPUT ;
    USE SIGNAL ;
    ANTENNAGATEAREA 0.180700 ;
    PORT
      LAYER Metal2 ;
        RECT 100.120 74.780 100.520 75.180 ;
    END
  END S4END[13]
  PIN S4END[14]
    DIRECTION INPUT ;
    USE SIGNAL ;
    ANTENNAGATEAREA 0.180700 ;
    PORT
      LAYER Metal2 ;
        RECT 101.080 74.780 101.480 75.180 ;
    END
  END S4END[14]
  PIN S4END[15]
    DIRECTION INPUT ;
    USE SIGNAL ;
    ANTENNAGATEAREA 0.180700 ;
    PORT
      LAYER Metal2 ;
        RECT 102.040 74.780 102.440 75.180 ;
    END
  END S4END[15]
  PIN S4END[1]
    DIRECTION INPUT ;
    USE SIGNAL ;
    ANTENNAGATEAREA 0.180700 ;
    PORT
      LAYER Metal2 ;
        RECT 88.600 74.780 89.000 75.180 ;
    END
  END S4END[1]
  PIN S4END[2]
    DIRECTION INPUT ;
    USE SIGNAL ;
    ANTENNAGATEAREA 0.180700 ;
    PORT
      LAYER Metal2 ;
        RECT 89.560 74.780 89.960 75.180 ;
    END
  END S4END[2]
  PIN S4END[3]
    DIRECTION INPUT ;
    USE SIGNAL ;
    ANTENNAGATEAREA 0.180700 ;
    PORT
      LAYER Metal2 ;
        RECT 90.520 74.780 90.920 75.180 ;
    END
  END S4END[3]
  PIN S4END[4]
    DIRECTION INPUT ;
    USE SIGNAL ;
    ANTENNAGATEAREA 0.180700 ;
    PORT
      LAYER Metal2 ;
        RECT 91.480 74.780 91.880 75.180 ;
    END
  END S4END[4]
  PIN S4END[5]
    DIRECTION INPUT ;
    USE SIGNAL ;
    ANTENNAGATEAREA 0.180700 ;
    PORT
      LAYER Metal2 ;
        RECT 92.440 74.780 92.840 75.180 ;
    END
  END S4END[5]
  PIN S4END[6]
    DIRECTION INPUT ;
    USE SIGNAL ;
    ANTENNAGATEAREA 0.180700 ;
    PORT
      LAYER Metal2 ;
        RECT 93.400 74.780 93.800 75.180 ;
    END
  END S4END[6]
  PIN S4END[7]
    DIRECTION INPUT ;
    USE SIGNAL ;
    ANTENNAGATEAREA 0.180700 ;
    PORT
      LAYER Metal2 ;
        RECT 94.360 74.780 94.760 75.180 ;
    END
  END S4END[7]
  PIN S4END[8]
    DIRECTION INPUT ;
    USE SIGNAL ;
    ANTENNAGATEAREA 0.180700 ;
    PORT
      LAYER Metal2 ;
        RECT 95.320 74.780 95.720 75.180 ;
    END
  END S4END[8]
  PIN S4END[9]
    DIRECTION INPUT ;
    USE SIGNAL ;
    ANTENNAGATEAREA 0.180700 ;
    PORT
      LAYER Metal2 ;
        RECT 96.280 74.780 96.680 75.180 ;
    END
  END S4END[9]
  PIN UserCLK
    DIRECTION INPUT ;
    USE SIGNAL ;
    ANTENNAGATEAREA 0.180700 ;
    PORT
      LAYER Metal3 ;
        RECT 0.000 1.900 0.400 2.300 ;
    END
  END UserCLK
  PIN UserCLKo
    DIRECTION OUTPUT ;
    USE SIGNAL ;
    ANTENNADIFFAREA 2.724000 ;
    PORT
      LAYER Metal3 ;
        RECT 136.400 1.900 136.800 2.300 ;
    END
  END UserCLKo
  PIN VGND
    DIRECTION INOUT ;
    USE GROUND ;
    PORT
      LAYER Metal4 ;
        RECT 15.380 0.000 16.380 75.180 ;
    END
    PORT
      LAYER Metal4 ;
        RECT 65.380 0.000 66.380 75.180 ;
    END
    PORT
      LAYER Metal4 ;
        RECT 115.380 0.000 116.380 75.180 ;
    END
  END VGND
  PIN VPWR
    DIRECTION INOUT ;
    USE POWER ;
    PORT
      LAYER Metal4 ;
        RECT 12.380 0.000 13.380 75.180 ;
    END
    PORT
      LAYER Metal4 ;
        RECT 62.380 0.000 63.380 75.180 ;
    END
    PORT
      LAYER Metal4 ;
        RECT 112.380 0.000 113.380 75.180 ;
    END
  END VPWR
  OBS
      LAYER GatPoly ;
        RECT 2.880 3.630 133.920 68.190 ;
      LAYER Metal1 ;
        RECT 2.880 3.560 133.920 68.260 ;
      LAYER Metal2 ;
        RECT 2.810 74.570 2.950 74.905 ;
        RECT 3.770 74.570 3.910 74.905 ;
        RECT 4.730 74.570 4.870 74.905 ;
        RECT 5.690 74.570 8.710 74.905 ;
        RECT 9.530 74.570 9.670 74.905 ;
        RECT 10.490 74.570 10.630 74.905 ;
        RECT 11.450 74.570 11.590 74.905 ;
        RECT 12.410 74.570 12.550 74.905 ;
        RECT 13.370 74.570 13.510 74.905 ;
        RECT 14.330 74.570 14.470 74.905 ;
        RECT 15.290 74.570 15.430 74.905 ;
        RECT 16.250 74.570 20.230 74.905 ;
        RECT 21.050 74.570 21.190 74.905 ;
        RECT 22.010 74.570 22.150 74.905 ;
        RECT 22.970 74.570 23.110 74.905 ;
        RECT 23.930 74.570 24.070 74.905 ;
        RECT 24.890 74.570 25.030 74.905 ;
        RECT 25.850 74.570 25.990 74.905 ;
        RECT 26.810 74.570 26.950 74.905 ;
        RECT 27.770 74.570 33.670 74.905 ;
        RECT 34.490 74.570 34.630 74.905 ;
        RECT 35.450 74.570 35.590 74.905 ;
        RECT 36.410 74.570 36.550 74.905 ;
        RECT 37.370 74.570 37.510 74.905 ;
        RECT 38.330 74.570 38.470 74.905 ;
        RECT 39.290 74.570 39.430 74.905 ;
        RECT 40.250 74.570 40.390 74.905 ;
        RECT 41.210 74.570 41.350 74.905 ;
        RECT 42.170 74.570 42.310 74.905 ;
        RECT 43.130 74.570 43.270 74.905 ;
        RECT 44.090 74.570 44.230 74.905 ;
        RECT 45.050 74.570 45.190 74.905 ;
        RECT 46.010 74.570 46.150 74.905 ;
        RECT 46.970 74.570 47.110 74.905 ;
        RECT 47.930 74.570 48.070 74.905 ;
        RECT 48.890 74.570 54.790 74.905 ;
        RECT 55.610 74.570 55.750 74.905 ;
        RECT 56.570 74.570 56.710 74.905 ;
        RECT 57.530 74.570 57.670 74.905 ;
        RECT 58.490 74.570 61.510 74.905 ;
        RECT 62.330 74.570 62.470 74.905 ;
        RECT 63.290 74.570 63.430 74.905 ;
        RECT 64.250 74.570 64.390 74.905 ;
        RECT 65.210 74.570 65.350 74.905 ;
        RECT 66.170 74.570 66.310 74.905 ;
        RECT 67.130 74.570 67.270 74.905 ;
        RECT 68.090 74.570 68.230 74.905 ;
        RECT 69.050 74.570 73.030 74.905 ;
        RECT 73.850 74.570 73.990 74.905 ;
        RECT 74.810 74.570 74.950 74.905 ;
        RECT 75.770 74.570 75.910 74.905 ;
        RECT 76.730 74.570 76.870 74.905 ;
        RECT 77.690 74.570 77.830 74.905 ;
        RECT 78.650 74.570 78.790 74.905 ;
        RECT 79.610 74.570 79.750 74.905 ;
        RECT 80.570 74.570 87.430 74.905 ;
        RECT 88.250 74.570 88.390 74.905 ;
        RECT 89.210 74.570 89.350 74.905 ;
        RECT 90.170 74.570 90.310 74.905 ;
        RECT 91.130 74.570 91.270 74.905 ;
        RECT 92.090 74.570 92.230 74.905 ;
        RECT 93.050 74.570 93.190 74.905 ;
        RECT 94.010 74.570 94.150 74.905 ;
        RECT 94.970 74.570 95.110 74.905 ;
        RECT 95.930 74.570 96.070 74.905 ;
        RECT 96.890 74.570 97.030 74.905 ;
        RECT 97.850 74.570 97.990 74.905 ;
        RECT 98.810 74.570 98.950 74.905 ;
        RECT 99.770 74.570 99.910 74.905 ;
        RECT 100.730 74.570 100.870 74.905 ;
        RECT 101.690 74.570 101.830 74.905 ;
        RECT 102.650 74.570 112.390 74.905 ;
        RECT 113.210 74.570 113.350 74.905 ;
        RECT 114.170 74.570 114.310 74.905 ;
        RECT 115.130 74.570 115.270 74.905 ;
        RECT 116.090 74.570 116.230 74.905 ;
        RECT 117.050 74.570 117.190 74.905 ;
        RECT 118.010 74.570 118.150 74.905 ;
        RECT 118.970 74.570 119.110 74.905 ;
        RECT 119.930 74.570 120.070 74.905 ;
        RECT 120.890 74.570 121.030 74.905 ;
        RECT 121.850 74.570 121.990 74.905 ;
        RECT 122.810 74.570 122.950 74.905 ;
        RECT 123.770 74.570 123.910 74.905 ;
        RECT 124.730 74.570 124.870 74.905 ;
        RECT 125.690 74.570 125.830 74.905 ;
        RECT 126.650 74.570 126.790 74.905 ;
        RECT 127.610 74.570 127.750 74.905 ;
        RECT 128.570 74.570 128.710 74.905 ;
        RECT 129.530 74.570 129.670 74.905 ;
        RECT 130.490 74.570 130.630 74.905 ;
        RECT 131.450 74.570 133.060 74.905 ;
        RECT 2.295 0.610 133.060 74.570 ;
        RECT 2.295 0.275 4.870 0.610 ;
        RECT 5.690 0.275 11.590 0.610 ;
        RECT 12.410 0.275 18.310 0.610 ;
        RECT 19.130 0.275 25.030 0.610 ;
        RECT 25.850 0.275 31.750 0.610 ;
        RECT 32.570 0.275 38.470 0.610 ;
        RECT 39.290 0.275 45.190 0.610 ;
        RECT 46.010 0.275 51.910 0.610 ;
        RECT 52.730 0.275 58.630 0.610 ;
        RECT 59.450 0.275 65.350 0.610 ;
        RECT 66.170 0.275 72.070 0.610 ;
        RECT 72.890 0.275 78.790 0.610 ;
        RECT 79.610 0.275 85.510 0.610 ;
        RECT 86.330 0.275 92.230 0.610 ;
        RECT 93.050 0.275 98.950 0.610 ;
        RECT 99.770 0.275 105.670 0.610 ;
        RECT 106.490 0.275 112.390 0.610 ;
        RECT 113.210 0.275 119.110 0.610 ;
        RECT 119.930 0.275 125.830 0.610 ;
        RECT 126.650 0.275 132.550 0.610 ;
      LAYER Metal3 ;
        RECT 0.380 65.510 136.420 74.860 ;
        RECT 0.610 64.690 136.190 65.510 ;
        RECT 0.380 63.830 136.420 64.690 ;
        RECT 0.610 63.010 136.190 63.830 ;
        RECT 0.380 62.150 136.420 63.010 ;
        RECT 0.610 61.330 136.190 62.150 ;
        RECT 0.380 60.470 136.420 61.330 ;
        RECT 0.610 59.650 136.190 60.470 ;
        RECT 0.380 58.790 136.420 59.650 ;
        RECT 0.610 57.970 136.190 58.790 ;
        RECT 0.380 57.110 136.420 57.970 ;
        RECT 0.610 56.290 136.190 57.110 ;
        RECT 0.380 55.430 136.420 56.290 ;
        RECT 0.610 54.610 136.190 55.430 ;
        RECT 0.380 53.750 136.420 54.610 ;
        RECT 0.610 52.930 136.190 53.750 ;
        RECT 0.380 52.070 136.420 52.930 ;
        RECT 0.610 51.250 136.190 52.070 ;
        RECT 0.380 50.390 136.420 51.250 ;
        RECT 0.610 49.570 136.190 50.390 ;
        RECT 0.380 48.710 136.420 49.570 ;
        RECT 0.610 47.890 136.190 48.710 ;
        RECT 0.380 47.030 136.420 47.890 ;
        RECT 0.610 46.210 136.190 47.030 ;
        RECT 0.380 45.350 136.420 46.210 ;
        RECT 0.610 44.530 136.190 45.350 ;
        RECT 0.380 43.670 136.420 44.530 ;
        RECT 0.610 42.850 136.190 43.670 ;
        RECT 0.380 41.990 136.420 42.850 ;
        RECT 0.610 41.170 136.190 41.990 ;
        RECT 0.380 40.310 136.420 41.170 ;
        RECT 0.610 39.490 136.190 40.310 ;
        RECT 0.380 38.630 136.420 39.490 ;
        RECT 0.610 37.810 136.190 38.630 ;
        RECT 0.380 36.950 136.420 37.810 ;
        RECT 0.610 36.130 136.190 36.950 ;
        RECT 0.380 35.270 136.420 36.130 ;
        RECT 0.610 34.450 136.190 35.270 ;
        RECT 0.380 33.590 136.420 34.450 ;
        RECT 0.610 32.770 136.190 33.590 ;
        RECT 0.380 31.910 136.420 32.770 ;
        RECT 0.610 31.090 136.190 31.910 ;
        RECT 0.380 30.230 136.420 31.090 ;
        RECT 0.610 29.410 136.190 30.230 ;
        RECT 0.380 28.550 136.420 29.410 ;
        RECT 0.610 27.730 136.190 28.550 ;
        RECT 0.380 26.870 136.420 27.730 ;
        RECT 0.610 26.050 136.190 26.870 ;
        RECT 0.380 25.190 136.420 26.050 ;
        RECT 0.610 24.370 136.190 25.190 ;
        RECT 0.380 23.510 136.420 24.370 ;
        RECT 0.610 22.690 136.190 23.510 ;
        RECT 0.380 21.830 136.420 22.690 ;
        RECT 0.610 21.010 136.190 21.830 ;
        RECT 0.380 20.150 136.420 21.010 ;
        RECT 0.610 19.330 136.190 20.150 ;
        RECT 0.380 18.470 136.420 19.330 ;
        RECT 0.610 17.650 136.190 18.470 ;
        RECT 0.380 16.790 136.420 17.650 ;
        RECT 0.610 15.970 136.190 16.790 ;
        RECT 0.380 15.110 136.420 15.970 ;
        RECT 0.610 14.290 136.190 15.110 ;
        RECT 0.380 13.430 136.420 14.290 ;
        RECT 0.610 12.610 136.190 13.430 ;
        RECT 0.380 2.510 136.420 12.610 ;
        RECT 0.610 1.690 136.190 2.510 ;
        RECT 0.380 0.320 136.420 1.690 ;
      LAYER Metal4 ;
        RECT 14.780 30.935 15.170 72.805 ;
        RECT 16.590 30.935 62.170 72.805 ;
        RECT 63.590 30.935 65.170 72.805 ;
        RECT 66.590 30.935 111.460 72.805 ;
      LAYER TopMetal1 ;
        RECT 33.260 71.500 72.820 73.140 ;
  END
END S_term_RAM_IO
END LIBRARY

